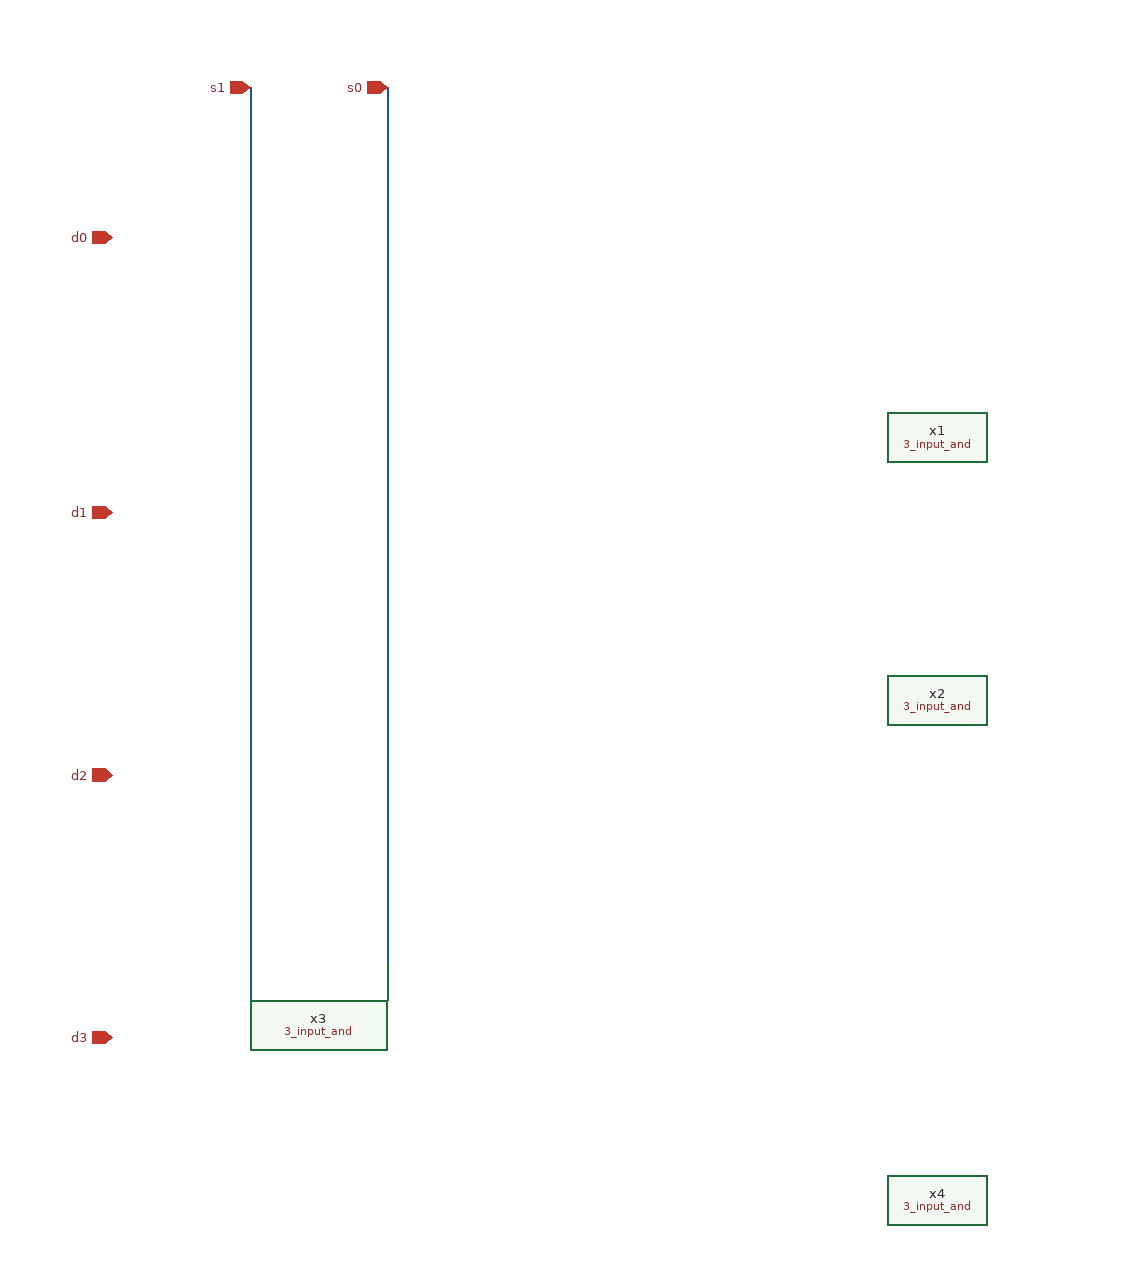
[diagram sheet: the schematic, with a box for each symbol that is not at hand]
v {xschem version=3.4.7 file_version=1.2}
G {}
K {}
V {}
S {}
E {}
N 220 -1000 220 -270 {lab=s1}
N 330 -1000 330 -300 {lab=s0}
C {title.sym} 40 50 0 0 {name=l1 author="The Digimons"}
C {ipin.sym} 110 -880 0 0 {name=p1 lab=d0}
C {ipin.sym} 110 -660 0 0 {name=p2 lab=d1}
C {ipin.sym} 110 -450 0 0 {name=p3 lab=d2}
C {ipin.sym} 110 -240 0 0 {name=p4 lab=d3}
C {ipin.sym} 220 -1000 1 0 {name=p5 lab=s1}
C {ipin.sym} 330 -1000 1 0 {name=p6 lab=s0}
C {3_input_and.sym} 770 -720 0 0 {name=x1}
C {3_input_and.sym} 770 -510 0 0 {name=x2}
C {3_input_and.sym} 770 -300 0 0 {name=x3}
C {3_input_and.sym} 770 -110 0 0 {name=x4}
